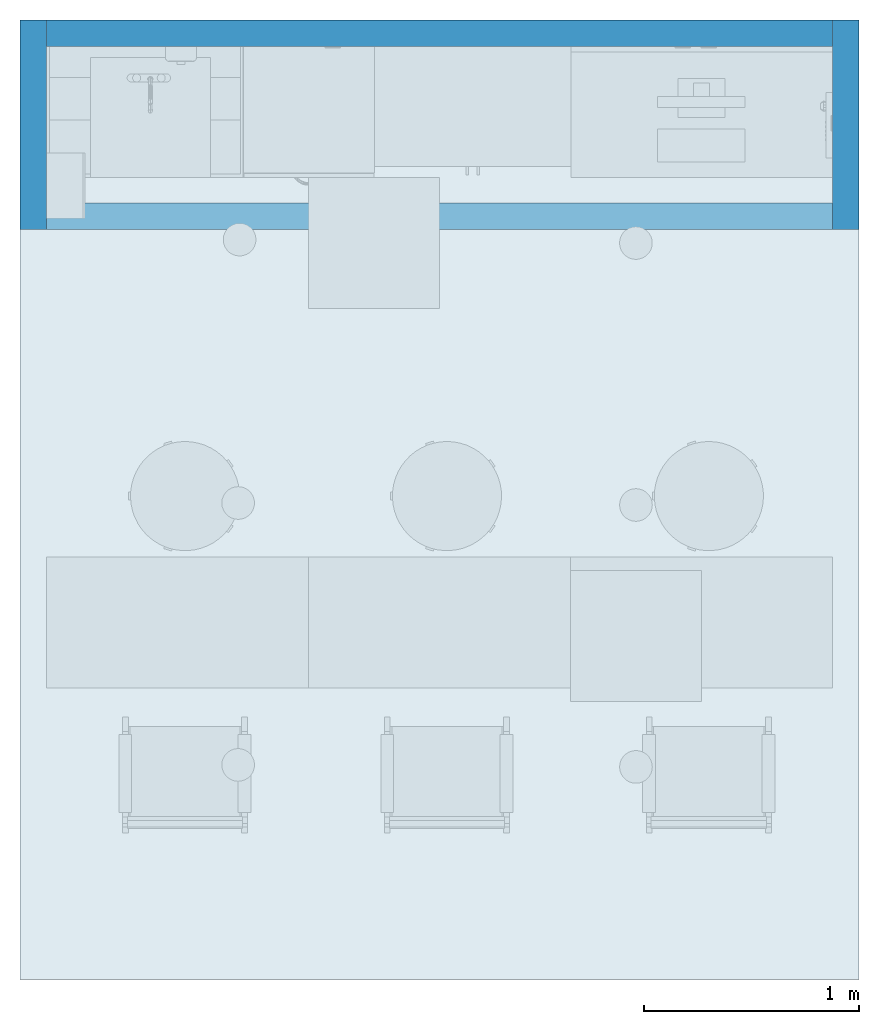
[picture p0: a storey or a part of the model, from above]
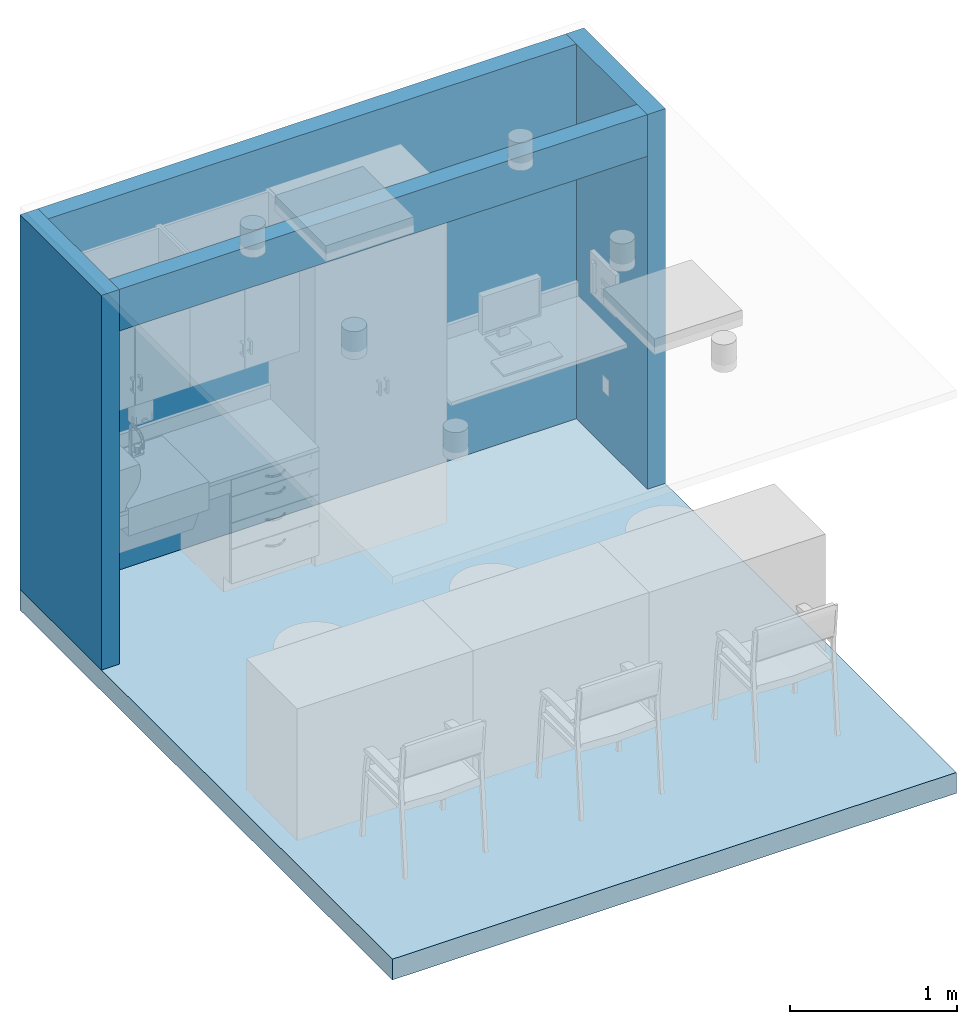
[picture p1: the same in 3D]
Properties of the parts of a building model (IFC2X3)

# File
Description: ViewDefinition [CoordinationView_V2.0]
File name: (ROOM CODE)
Time: 2018-06-28T13:18:59
Written by: The EXPRESS Data Manager Version 5.02.0100.07 : 28 Aug 2013
Made in: 20170223_1515(x64) - Exporter 18.0.0.420 - Alternate UI 18.0.0.420
Comment: STEP Physical File produced by: The EXPRESS Data Manager Version 5.02.0100.07 : 28 Aug 2013 * Module: EDMstepFileFactory/EDMstandAlone * Creation date: Thu Jun 28 13:18:59 2018 * Host: L105-OKC * Database: C:\Users\jet\AppData\Local\Temp\{B88D2EB0-736B-444B-B505-6E204D8F8703}\ifc * Database version: 5507 * Database creation date: Thu Jun 28 13:18:57 2018 * Schema: IFC2X3 * Model: DataRepository.ifc * Model creation date: Thu Jun 28 13:18:58 2018 * Header model: DataRepository.ifc_HeaderModel * Header model creation date: Thu Jun 28 13:18:58 2018 * EDMuser: sdai-user * EDMgroup: sdai-group * License ID and type: 5605 : Permanent license. Expiry date: * EDMstepFileFactory options: 020000

# IfcProject, (ROOM CODE)
LongName: ROOM NAME & AREA; Phase: DRAFT

# IfcSite, Default
RefLatitude: 42, 21, 31, 181945; RefLongitude: -71, -3, -24, -263305; RefElevation: 0 ft

# IfcBuilding, EYE CLINIC: OPTHALMOLOGY AND OPTOMETRY SERVICES (Ch. 233)
LongName: EYE CLINIC: OPTHALMOLOGY AND OPTOMETRY SERVICES (Ch. 233)
Pset_BuildingCommon - NumberOfStoreys: 1

# IfcBuildingStorey, DATUM
In: EYE CLINIC: OPTHALMOLOGY AND OPTOMETRY SERVICES (Ch. 233)
LongName: DATUM; Elevation: 0 ft

# IfcSpace, (OPFD1)
In: DATUM
LongName: FITTING AND DISPENSING AREA, EYEGLASSES; InteriorOrExteriorSpace: INTERNAL
Pset_SpaceCommon - Reference: FITTING AND DISPENSING AREA, EYEGLASSES (OPFD1); Category: Rooms

# IfcBuildingElementProxy: 24" x 24", Supply Diffuser:24" x 24":2005727
In: (OPFD1)
Type - Classification: D3040100 Air Distribution Systems (Uniformat)
Pset_BuildingElementProxyCommon - Reference: 24" x 24"

# IfcBuildingElementProxy: 24" x 24", Return Register:24" x 24":2006048
In: (OPFD1)
Type - Classification: D3040200 Exhaust Ventilation Systems (Uniformat)
Pset_BuildingElementProxyCommon - Reference: 24" x 24"

# IfcBuildingElementProxy: 3', C02Q01 - Cabinet, ADA Sink Support:3':2440051
In: (OPFD1)
Type - Classification: CC (Uniformat)
Pset_BuildingElementProxyCommon - Reference: 3'
Pset_ManufacturerTypeInformation - Manufacturer: Herman Miller, Inc.

# IfcBuildingElementProxy: 35"H x 24"D x 24"W Key Alike, C02D0 - Cabinet Base 4-Drawer:35"H x 24"D x 24"W Key Alike:2438989
In: (OPFD1)
Type - Classification: VV (Uniformat)
Pset_BuildingElementProxyCommon - Reference: 35"H x 24"D x 24"W Key Alike
Pset_ManufacturerTypeInformation - Manufacturer: Herman Miller, Inc.

# IfcBuildingElementProxy: A1014 - Telephone, Wall Mounted, 1 Line, With Speaker 12"x 12", A1014 - Telephone, Wall Mounted, 1 Line, With Speaker 12 x 12:A1014 - Telephone, Wall Mounted, 1 Line, With Speaker 12"x 12":2342066
In: (OPFD1)
Pset_BuildingElementProxyCommon - Reference: A1014 - Telephone, Wall Mounted, 1 Line, With Speaker 12"x 12"

# IfcBuildingElementProxy: A5075 - Dispenser, Soap, A5075 - Dispenser, Soap:A5075 - Dispenser, Soap:2002874
In: (OPFD1)
Type - Classification: VV (Uniformat)
Pset_BuildingElementProxyCommon - Reference: A5075 - Dispenser, Soap

# IfcBuildingElementProxy: A5082 - Dispenser, Paper Towel, Sensor, Hands Free, A5082 - Dispenser, Paper Towel, Sensor, Hands Free:A5082 - Dispenser, Paper Towel, Sensor, Hands Free:2003005
In: (OPFD1)
Type - Classification: CC (Uniformat)
Pset_BuildingElementProxyCommon - Reference: A5082 - Dispenser, Paper Towel, Sensor, Hands Free

# IfcBuildingElementProxy: CD030 - Cabinet, W-H, 2 Shelf, 2 DO, Sloping Top, 38x30x13 (2)
In: (OPFD1)
Type - Material: Default metal
Pset_BuildingElementProxyCommon - Reference: CD030 - Cabinet, W-H, 2 Shelf, 2 DO, Sloping Top, 38x30x13
Name (CD030 - Cabinet, W-H, 2 Shelf, 2 DO, Sloping Top, 38x30x13:CD030 - Cabinet, W-H, 2 Shelf, 2 DO, Sloping Top, 38x30x13:...)
2356052
2356119

# IfcBuildingElementProxy: CS090 - Sink, SS, Single Compartment, 7.5x19x16 ID, CS090 - Sink, SS, Single Compartment, 7.5x19x16 ID:CS090 - Sink, SS, Single Compartment, 7.5x19x16 ID:2003400
In: (OPFD1)
Type - Material: EquipSpace, Metal - Steel, Polished, Default
Pset_BuildingElementProxyCommon - Reference: CS090 - Sink, SS, Single Compartment, 7.5x19x16 ID

# IfcBuildingElementProxy: CT020 - Countertop, Solid Surface - No Opening (2)
In: (OPFD1)
Type - Material: CounterTopFinish
Pset_BuildingElementProxyCommon - Reference: CT020 - Countertop, Solid Surface - No Opening
Name (CT020 - Countertop, Solid Surface - No Opening:CT020 - Countertop, Solid Surface - No Opening:...)
2383906
2384364

# IfcBuildingElementProxy: CW140 - Cabinet, Floor Standing, 5 SH, 2 GDO, ST, 98x36x22, CW140 - Cabinet, Floor Standing, 5 SH, 2 GDO, ST, 98x36x22:CW140 - Cabinet, Floor Standing, 5 SH, 2 GDO, ST, 98x36x22:2035417
In: (OPFD1)
Type - Material: Glass, Default metal, EquipSpace
Pset_BuildingElementProxyCommon - Reference: CW140 - Cabinet, Floor Standing, 5 SH, 2 GDO, ST, 98x36x22

# IfcBuildingElementProxy: Duplex (2)
In: (OPFD1)
Pset_BuildingElementProxyCommon - Reference: Duplex
Name (Outlet, Duplex, Wall:Duplex:...)
2381981
2478464

# IfcBuildingElementProxy: E0703 - Table, Process, Adj Height, 5 Drawer, 48W x 24D (3)
In: (OPFD1)
Type - Material: EquipSpace
Pset_BuildingElementProxyCommon - Reference: E0703 - Table, Process, Adj Height, 5 Drawer, 48W x 24D
Name (E0703 - Table, Process, Adj Height, 5 Drawer, 48W x 24D:E0703 - Table, Process, Adj Height, 5 Drawer, 48W x 24D:...)
2037926
2348211
2348241

# IfcBuildingElementProxy: F0205 - Side Chair with Arms (3)
In: (OPFD1)
Type - Classification: VV (Uniformat)
Pset_BuildingElementProxyCommon - Reference: F0205 - Side Chair with Arms
Name (F0205 - Side Chair with Arms:F0205 - Side Chair with Arms:...)
2003647
2348617
2348641

# IfcBuildingElementProxy: F0340 - Stool, Self Adjusting (3)
In: (OPFD1)
Type - Classification: VV (Uniformat); Material: Stool caster, Stool metal, Stool cushion
Pset_BuildingElementProxyCommon - Reference: F0340 - Stool, Self Adjusting
Name (F0340 - Stool, Self Adjusting:F0340 - Stool, Self Adjusting:...)
2003867
2003982
2339343

# IfcBuildingElementProxy: M1801 - Computer, Microprocessing, With Flat Panel Monitor, M1801 - Computer, Microprocessing, With Flat Panel Monitor:M1801 - Computer, Microprocessing, With Flat Panel Monitor:2004246
In: (OPFD1)
Type - Classification: VV (Uniformat)
Pset_BuildingElementProxyCommon - Reference: M1801 - Computer, Microprocessing, With Flat Panel Monitor

# IfcBuildingElementProxy: Telephone/Data (2)
In: (OPFD1)
Pset_BuildingElementProxyCommon - Reference: Telephone/Data
Name (Outlet, Communications:Telephone/Data:...)
2382068
2459285

# IfcCovering: Compound Ceiling:2' x 2' ACT System, Compound Ceiling:2' x 2' ACT System:2005691
In: DATUM
PredefinedType: CEILING; Classification: C3030210 Suspended Ceilings - Acoustical (Uniformat); Material: Default 0.135417 ft, Acoustic Ceiling Tile 24 x 24 0.0520833 ft
Pset_CoveringCommon - Reference: 2' x 2' ACT System; Finish: Acoustic Ceiling Tile 24 x 24;; TotalThickness: 0.1875 ft

# IfcFlowTerminal: 6" (6)
In: (OPFD1)
Type - Classification: D5020220 Lighting - Incandescent (Uniformat)
Pset_DistributionFlowElementCommon - Reference: 6"
Name (Downlight - Recessed Can:6":...)
2349818
2350070
2350300
2350301
2483170
2483171

# IfcSlab: Floor:Generic - 6", Floor:Generic - 6":2002804
In: DATUM
PredefinedType: FLOOR; Classification: B1010 Floor Construction (Uniformat); Material: Default Floor 0.5 ft
Pset_SlabCommon - Reference: Generic - 6"; IsExternal: no; LoadBearing: no; PitchAngle: 0 deg

# IfcWallStandardCase: Basic Wall:Interior - 4 7/8" (3)
In: DATUM
Type - PredefinedType: STANDARD; Material: Default Wall 0.40625 ft
Classification: B2010 Exterior Walls (Uniformat)
Pset_WallCommon - LoadBearing: no; Reference: Interior - 4 7/8"; ExtendToStructure: no; IsExternal: yes
Name (Basic Wall:Interior - 4 7/8":...)
2002820
2002823
2002826

# IfcWallStandardCase: Basic Wall:Interior - 4 7/8" Bulkhead, Basic Wall:Interior - 4 7/8" Bulkhead:2350899
In: DATUM
Type - PredefinedType: STANDARD; Material: Default Wall 0.40625 ft
Classification: B2010 Exterior Walls (Uniformat)
Pset_WallCommon - LoadBearing: no; ExtendToStructure: no; IsExternal: yes; Reference: Interior - 4 7/8" Bulkhead
